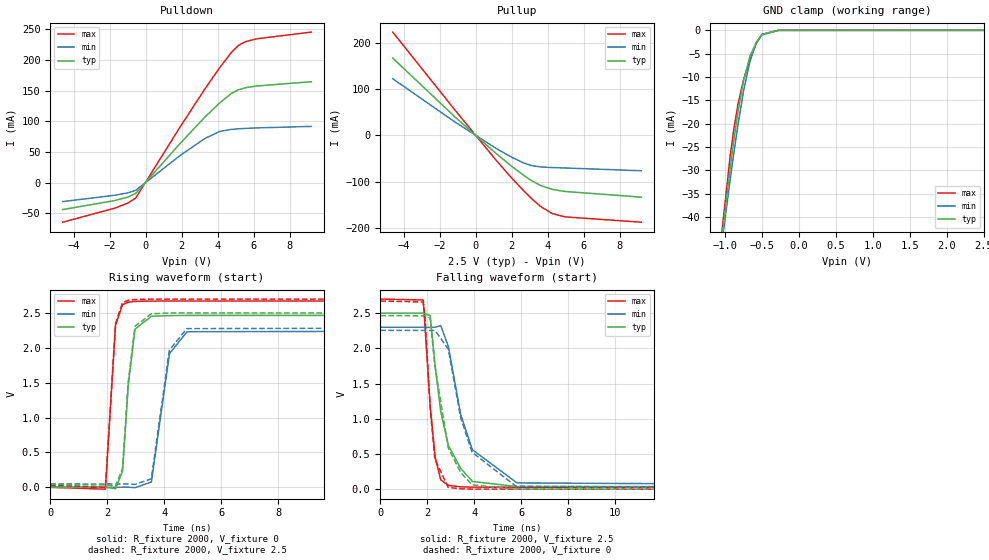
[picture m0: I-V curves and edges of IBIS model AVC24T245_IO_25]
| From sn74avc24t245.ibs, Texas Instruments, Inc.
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[Model]   AVC24T245_IO_25
Model_type  I/O
Vinl=0.7
Vinh=1.6
Enable   Active-Low
Vref =   0
Rref =   2000
Cref =   15p
Vmeas =   1.25
| variable   typ   min   max
C_comp   4.95pF   4.21pF   5.74pF
| C_pullup   4.12pF   3.17pF   5.55pF
| C_pulldown   4.24pF   3.76pF   4.72pF
| C_tri-state   4.95pF   4.21pF   5.74pF
[Temperature Range]   40   100   -40
| Ambient temperature   25   85   -40
[Voltage range]   2.5   2.3   2.7
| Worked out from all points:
|   slope of the pulldown table from 0 to 0.375 V, typ, clamps not added: 29.4 ohm
|   slope of the pullup table from 0 to 0.375 V, typ, clamps not added: 28.8 ohm
|   GND clamp passes 1 mA (typ) near -0.50 V on its own axis
|   rising waveform, R_fixture 2000, V_fixture 0: 20-80 % time 248ps typ, 381ps min, 174ps max; typ from 0 V to 2.46 V
|   falling waveform, R_fixture 2000, V_fixture 2.5: 20-80 % time 729ps typ, 1.03ns min, 343ps max; typ from 2.5 V to 0.036 V
|   rising waveform, R_fixture 2000, V_fixture 2.5: 20-80 % time 246ps typ, 377ps min, 174ps max; typ from 0.036 V to 2.5 V
|   falling waveform, R_fixture 2000, V_fixture 0: 20-80 % time 723ps typ, 1.03ns min, 335ps max; typ from 2.46 V to 0 V
[GND Clamp]
| AVC24T245_IO_25
|   Voltage   I(typ)   I(min)   I(max)
-4.6V     -597.8mA   -546.6mA   -662.5mA
-1.105V   -52.8mA    -53.15mA   -52.37mA
-1.08V    -49.35mA   -50.03mA   -48.48mA
-930mV    -29.5mA    -31.88mA   -26.82mA
-880mV    -23.45mA   -26.17mA   -21.02mA
-825mV    -17.44mA   -20.22mA   -15.81mA
-750mV    -10.86mA   -13.03mA   -10.61mA
-665mV    -5.629mA   -6.786mA   -6.326mA
-580mV    -2.642mA   -2.683mA   -2.914mA
-500mV    -988.4uA   -823.5uA   -890.7uA
-280mV    -5.263uA   -7.282uA   -1.131uA
2.5V      1.201nA    546.5nA    148.6pA
[Pulldown]
| AVC24T245_IO_25
|   Voltage   I(typ)   I(min)   I(max)
-4.6V     -43.76mA   -30.71mA   -64.27mA
-1.71V    -29.04mA   -20.44mA   -41.4mA
-985mV    -23.44mA   -16.53mA   -33.24mA
-545mV    -17.41mA   -12.35mA   -24.86mA
1.85V     61.76mA    42.85mA    87.78mA
3.295V    106.9mA    72.08mA    152.8mA
4.12V     130.1mA    83.49mA    187.5mA
4.755V    145.2mA    86.77mA    211.8mA
5.15V     151.2mA    87.75mA    223.4mA
5.55V     154.6mA    88.43mA    229.7mA
6.155V    157.4mA    89.2mA     234.2mA
9.2V      164.4mA    91.67mA    245.2mA
[Pullup]
| AVC24T245_IO_25
|   Voltage   I(typ)   I(min)   I(max)
-4.6V     167.2mA    122.6mA    223.3mA
-1.155V   40.55mA    29.45mA    55.44mA
1.195V    -40.71mA   -29.18mA   -56.05mA
2.025V    -67.14mA   -47.36mA   -92.77mA
2.69V     -86.59mA   -59.63mA   -120.2mA
3.115V    -97.78mA   -65.03mA   -136.5mA
3.61V     -108mA     -67.79mA   -153.3mA
4.245V    -116.2mA   -69.29mA   -168.4mA
4.95V     -120.8mA   -70.1mA    -175.7mA
9.2V      -133.1mA   -76.13mA   -187.2mA
[Ramp]
| AVC24T245_IO_25
| variable   typ   min   max
dV/dt_r   1.50/2.55E-10   1.37/3.90E-10   1.62/1.81E-10
dV/dt_f   1.49/7.33E-10   1.37/1.04E-09   1.61/3.44E-10
R_load = 2000
[Rising Waveform]
| AVC24T245_IO_25
R_fixture =   2000
C_fixture =   0
L_fixture =   0
V_fixture =   0
V_fixture_min = 0
V_fixture_max = 0
|   Time   V(typ)   V(min)   V(max)
0s        27.72nV    106.5nV    1.06nV
1.935ns   1.036mV    -41.18uV   -26.77mV
2.29ns    -21.47mV   -10.24uV   2.322V
2.535ns   229.6mV    1.658mV    2.619V
2.74ns    1.476V     1.798mV    2.655V
2.975ns   2.269V     -5.262mV   2.666V
3.55ns    2.453V     76.18mV    2.671V
4.185ns   2.463V     1.917V     2.672V
4.8ns     2.465V     2.231V     2.672V
29.99ns   2.465V     2.256V     2.672V
[Falling Waveform]
| AVC24T245_IO_25
R_fixture =   2000
C_fixture =   0
L_fixture =   0
V_fixture =   2.5
V_fixture_min = 2.3
V_fixture_max = 2.7
|   Time   V(typ)   V(min)   V(max)
0s        2.5V       2.3V       2.7V
1.83ns    2.499V     2.3V       2.687V
2.125ns   2.467V     2.298V     1.19V
2.335ns   1.757V     2.3V       459.7mV
2.575ns   1.104V     2.323V     132.3mV
2.9ns     622.5mV    2.029V     54.21mV
3.425ns   294.7mV    1.062V     32.74mV
3.925ns   109.8mV    560.2mV    28.7mV
5.825ns   37.16mV    88.79mV    27.64mV
29.99ns   36.05mV    46.86mV    27.62mV
[Rising Waveform]
| AVC24T245_IO_25
R_fixture =   2000
C_fixture =   0
L_fixture =   0
V_fixture =   2.5
V_fixture_min = 2.3
V_fixture_max = 2.7
|   Time   V(typ)   V(min)   V(max)
0s        36.05mV    46.86mV    27.62mV
1.935ns   37.09mV    46.82mV    864.3uV
2.29ns    14.58mV    46.85mV    2.35V
2.535ns   267.6mV    48.51mV    2.648V
2.74ns    1.523V     48.59mV    2.683V
2.975ns   2.309V     41.47mV    2.694V
3.545ns   2.489V     120mV      2.699V
4.18ns    2.499V     1.966V     2.7V
4.79ns    2.5V       2.276V     2.7V
29.99ns   2.5V       2.3V       2.7V
[Falling Waveform]
| AVC24T245_IO_25
R_fixture =   2000
C_fixture =   0
L_fixture =   0
V_fixture =   0
V_fixture_min = 0
V_fixture_max = 0
|   Time   V(typ)   V(min)   V(max)
0s        2.465V     2.256V     2.672V
1.83ns    2.463V     2.255V     2.659V
1.905ns   2.465V     2.255V     2.448V
2.125ns   2.431V     2.253V     1.153V
2.33ns    1.743V     2.256V     420.7mV
2.895ns   589.7mV    1.99V      25.55mV
3.42ns    238.5mV    1.022V     4.788mV
3.91ns    60.23mV    523.8mV    1.044mV
5.78ns    967.2uV    41.64mV    22.97uV
29.99ns   422.5nV    393.3nV    257nV
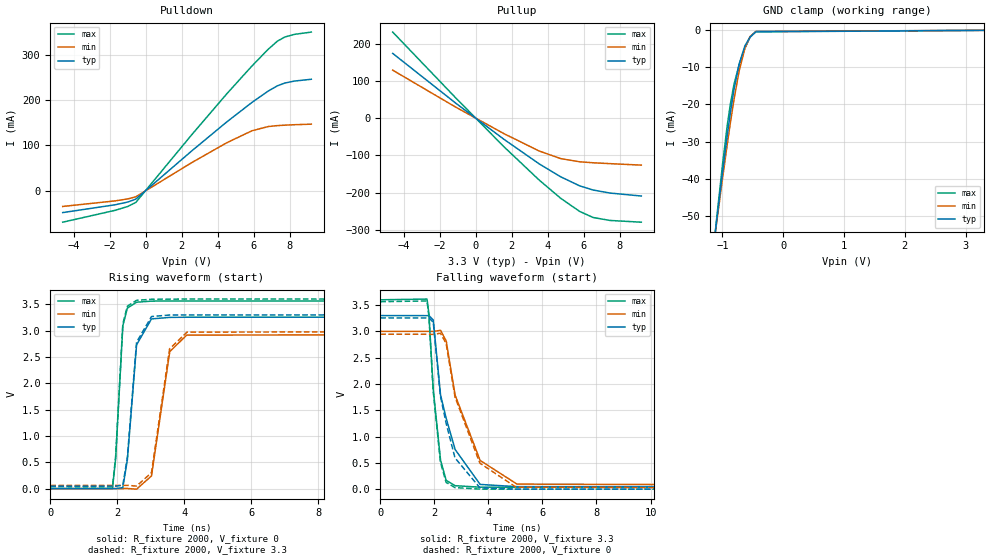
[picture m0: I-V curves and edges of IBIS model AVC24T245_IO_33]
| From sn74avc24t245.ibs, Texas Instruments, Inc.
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[Model]   AVC24T245_IO_33
Model_type  I/O
Vinl=0.8
Vinh=2.0
Enable   Active-Low
Vref =   0
Rref =   2000
Cref =   15p
Vmeas =   1.65
| variable   typ   min   max
C_comp   4.80pF   4.02pF   5.70pF
| C_pullup   3.86pF   2.95pF   5.16pF
| C_pulldown   4.06pF   3.58pF   4.65pF
| C_tri-state   4.80pF   4.02pF   5.70pF
[Temperature Range]   40   100   -40
| Ambient temperature   25   85   -40
[Voltage range]   3.3   3   3.6
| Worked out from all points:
|   slope of the pulldown table from 0 to 0.495 V, typ, clamps not added: 28.7 ohm
|   slope of the pullup table from 0 to 0.495 V, typ, clamps not added: 27.4 ohm
|   GND clamp passes 1 mA (typ) near -0.50 V on its own axis
|   rising waveform, R_fixture 2000, V_fixture 0: 20-80 % time 233ps typ, 352ps min, 163ps max; typ from 0 V to 3.26 V
|   falling waveform, R_fixture 2000, V_fixture 3.3: 20-80 % time 746ps typ, 998ps min, 333ps max; typ from 3.3 V to 0.046 V
|   rising waveform, R_fixture 2000, V_fixture 3.3: 20-80 % time 232ps typ, 351ps min, 162ps max; typ from 0.046 V to 3.3 V
|   falling waveform, R_fixture 2000, V_fixture 0: 20-80 % time 662ps typ, 998ps min, 328ps max; typ from 3.26 V to 0 V
[GND Clamp]
| AVC24T245_IO_33
|   Voltage   I(typ)   I(min)   I(max)
-4.6V     -597.8mA   -546.6mA   -662.5mA
-1.12V    -54.88mA   -55.04mA   -54.73mA
-1.09V    -50.72mA   -51.27mA   -50.03mA
-1V       -38.53mA   -40.19mA   -36.43mA
-920mV    -28.25mA   -30.71mA   -25.57mA
-870mV    -22.29mA   -25.06mA   -19.99mA
-810mV    -15.96mA   -18.69mA   -14.59mA
-725mV    -9.083mA   -10.96mA   -9.257mA
-630mV    -4.179mA   -4.838mA   -4.797mA
-545mV    -1.809mA   -1.649mA   -1.862mA
-450mV    -412.7uA   -343uA     -301.7uA
3.3V      1.631nA    2.398uA    228.2pA
[Pulldown]
| AVC24T245_IO_33
|   Voltage   I(typ)   I(min)   I(max)
-4.6V     -47.48mA   -33.99mA   -68.59mA
-1.68V    -30.25mA   -21.7mA    -42.42mA
-975mV    -24.15mA   -17.32mA   -33.81mA
-545mV    -17.86mA   -12.84mA   -25.24mA
2.54V     87.35mA    61.85mA    122.6mA
4.5V      151.6mA    105.9mA    213.3mA
5.905V    194.7mA    132.4mA    274.8mA
6.805V    219.6mA    141.6mA    311.5mA
7.315V    231.2mA    143.7mA    329.3mA
7.73V     237.3mA    144.7mA    338.5mA
8.275V    241.7mA    145.7mA    344.4mA
9.2V      245.6mA    146.9mA    349.3mA
[Pullup]
| AVC24T245_IO_33
|   Voltage   I(typ)   I(min)   I(max)
-4.6V     174.2mA    129.1mA    231.4mA
-1.105V   40.58mA    29.86mA    54.82mA
1.58V     -56.83mA   -41.58mA   -76.89mA
3.53V     -122.6mA   -88.07mA   -166.1mA
4.725V    -157.4mA   -108.5mA   -215.1mA
5.775V    -181.6mA   -117mA     -250.3mA
6.525V    -192.9mA   -119.7mA   -266.7mA
7.46V     -201mA     -122mA     -274.6mA
9.2V      -209mA     -126mA     -279.3mA
[Ramp]
| AVC24T245_IO_33
| variable   typ   min   max
dV/dt_r   1.97/2.38E-10   1.79/3.63E-10   2.15/1.70E-10
dV/dt_f   1.96/7.47E-10   1.78/9.99E-10   2.15/3.35E-10
R_load = 2000
[Rising Waveform]
| AVC24T245_IO_33
R_fixture =   2000
C_fixture =   0
L_fixture =   0
V_fixture =   0
V_fixture_min = 0
V_fixture_max = 0
|   Time   V(typ)   V(min)   V(max)
0s        38nV       120.5nV    1.922nV
1.855ns   2.06mV     -31.08uV   -2.575mV
1.95ns    -962.9uV   17.61uV    566.9mV
2.165ns   19.58mV    871.4uV    3.091V
2.3ns     546.6mV    2.522mV    3.428V
2.575ns   2.732V     -10.6mV    3.54V
3.02ns    3.223V     240.9mV    3.561V
3.565ns   3.252V     2.602V     3.564V
4.07ns    3.255V     2.915V     3.564V
29.99ns   3.256V     2.946V     3.564V
[Falling Waveform]
| AVC24T245_IO_33
R_fixture =   2000
C_fixture =   0
L_fixture =   0
V_fixture =   3.3
V_fixture_min = 3
V_fixture_max = 3.6
|   Time   V(typ)   V(min)   V(max)
0s        3.3V       3V         3.6V
1.73ns    3.299V     2.999V     3.614V
1.8ns     3.302V     2.999V     3.325V
1.96ns    3.216V     2.998V     1.889V
2.23ns    1.792V     3.019V     552.8mV
2.44ns    1.344V     2.817V     166.5mV
2.77ns    753.9mV    1.787V     65.86mV
3.695ns   90.08mV    545.9mV    37.54mV
5.06ns    47.7mV     95.89mV    36.37mV
29.99ns   46.48mV    58.85mV    36.33mV
[Rising Waveform]
| AVC24T245_IO_33
R_fixture =   2000
C_fixture =   0
L_fixture =   0
V_fixture =   3.3
V_fixture_min = 3
V_fixture_max = 3.6
|   Time   V(typ)   V(min)   V(max)
0s        46.48mV    58.85mV    36.33mV
1.855ns   48.54mV    58.82mV    33.68mV
1.95ns    45.49mV    58.87mV    603.6mV
2.165ns   66.27mV    59.73mV    3.13V
2.3ns     595.4mV    61.37mV    3.465V
2.575ns   2.781V     48.09mV    3.576V
3.02ns    3.268V     303mV      3.596V
3.56ns    3.297V     2.654V     3.599V
4.08ns    3.299V     2.972V     3.6V
29.99ns   3.3V       3V         3.6V
[Falling Waveform]
| AVC24T245_IO_33
R_fixture =   2000
C_fixture =   0
L_fixture =   0
V_fixture =   0
V_fixture_min = 0
V_fixture_max = 0
|   Time   V(typ)   V(min)   V(max)
0s        3.256V     2.946V     3.564V
1.73ns    3.255V     2.945V     3.578V
1.8ns     3.258V     2.944V     3.291V
1.96ns    3.172V     2.943V     1.861V
2.225ns   1.769V     2.964V     515.2mV
2.435ns   1.258V     2.773V     129.6mV
2.765ns   593.9mV    1.751V     29.34mV
3.685ns   26.48mV    494.2mV    1.215mV
5.025ns   755uV      37.25mV    46.84uV
29.99ns   531.5nV    793.9nV    237.6nV
